VERSION 5.7 ;
  NOWIREEXTENSIONATPIN ON ;
  DIVIDERCHAR "/" ;
  BUSBITCHARS "[]" ;
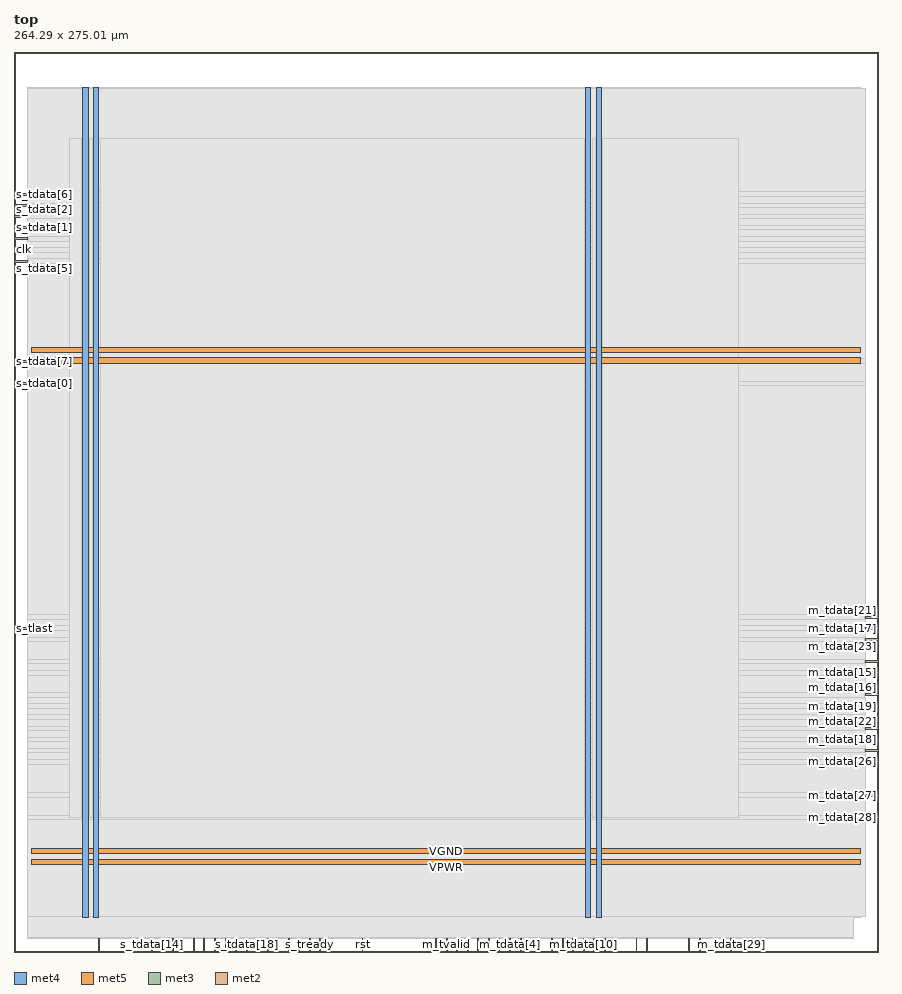
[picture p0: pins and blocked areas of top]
MACRO top
  CLASS BLOCK ;
  FOREIGN top ;
  ORIGIN 0.000 0.000 ;
  SIZE 264.290 BY 275.010 ;
  PIN VGND
    DIRECTION INOUT ;
    USE GROUND ;
    PORT
      LAYER met4 ;
        RECT 24.340 10.640 25.940 264.080 ;
    END
    PORT
      LAYER met4 ;
        RECT 177.940 10.640 179.540 264.080 ;
    END
    PORT
      LAYER met5 ;
        RECT 5.280 30.030 258.760 31.630 ;
    END
    PORT
      LAYER met5 ;
        RECT 5.280 183.210 258.760 184.810 ;
    END
  END VGND
  PIN VPWR
    DIRECTION INOUT ;
    USE POWER ;
    PORT
      LAYER met4 ;
        RECT 21.040 10.640 22.640 264.080 ;
    END
    PORT
      LAYER met4 ;
        RECT 174.640 10.640 176.240 264.080 ;
    END
    PORT
      LAYER met5 ;
        RECT 5.280 26.730 258.760 28.330 ;
    END
    PORT
      LAYER met5 ;
        RECT 5.280 179.910 258.760 181.510 ;
    END
  END VPWR
  PIN clk
    DIRECTION INPUT ;
    USE SIGNAL ;
    ANTENNAGATEAREA 0.852000 ;
    PORT
      LAYER met3 ;
        RECT 0.000 214.240 4.000 214.840 ;
    END
  END clk
  PIN m_tdata[0]
    DIRECTION OUTPUT ;
    USE SIGNAL ;
    ANTENNADIFFAREA 0.445500 ;
    PORT
      LAYER met2 ;
        RECT 138.550 0.000 138.830 4.000 ;
    END
  END m_tdata[0]
  PIN m_tdata[10]
    DIRECTION OUTPUT ;
    USE SIGNAL ;
    ANTENNADIFFAREA 0.445500 ;
    PORT
      LAYER met2 ;
        RECT 173.970 0.000 174.250 4.000 ;
    END
  END m_tdata[10]
  PIN m_tdata[11]
    DIRECTION OUTPUT ;
    USE SIGNAL ;
    ANTENNADIFFAREA 0.445500 ;
    PORT
      LAYER met2 ;
        RECT 177.190 0.000 177.470 4.000 ;
    END
  END m_tdata[11]
  PIN m_tdata[12]
    DIRECTION OUTPUT ;
    USE SIGNAL ;
    ANTENNADIFFAREA 0.445500 ;
    PORT
      LAYER met2 ;
        RECT 193.290 0.000 193.570 4.000 ;
    END
  END m_tdata[12]
  PIN m_tdata[13]
    DIRECTION OUTPUT ;
    USE SIGNAL ;
    ANTENNADIFFAREA 0.445500 ;
    PORT
      LAYER met2 ;
        RECT 190.070 0.000 190.350 4.000 ;
    END
  END m_tdata[13]
  PIN m_tdata[14]
    DIRECTION OUTPUT ;
    USE SIGNAL ;
    ANTENNADIFFAREA 0.445500 ;
    PORT
      LAYER met2 ;
        RECT 180.410 0.000 180.690 4.000 ;
    END
  END m_tdata[14]
  PIN m_tdata[15]
    DIRECTION OUTPUT ;
    USE SIGNAL ;
    ANTENNADIFFAREA 0.445500 ;
    PORT
      LAYER met3 ;
        RECT 260.290 85.040 264.290 85.640 ;
    END
  END m_tdata[15]
  PIN m_tdata[16]
    DIRECTION OUTPUT ;
    USE SIGNAL ;
    ANTENNADIFFAREA 0.445500 ;
    PORT
      LAYER met3 ;
        RECT 260.290 78.240 264.290 78.840 ;
    END
  END m_tdata[16]
  PIN m_tdata[17]
    DIRECTION OUTPUT ;
    USE SIGNAL ;
    ANTENNADIFFAREA 0.445500 ;
    PORT
      LAYER met3 ;
        RECT 260.290 98.640 264.290 99.240 ;
    END
  END m_tdata[17]
  PIN m_tdata[18]
    DIRECTION OUTPUT ;
    USE SIGNAL ;
    ANTENNADIFFAREA 0.445500 ;
    PORT
      LAYER met3 ;
        RECT 260.290 64.640 264.290 65.240 ;
    END
  END m_tdata[18]
  PIN m_tdata[19]
    DIRECTION OUTPUT ;
    USE SIGNAL ;
    ANTENNADIFFAREA 0.445500 ;
    PORT
      LAYER met3 ;
        RECT 260.290 74.840 264.290 75.440 ;
    END
  END m_tdata[19]
  PIN m_tdata[1]
    DIRECTION OUTPUT ;
    USE SIGNAL ;
    ANTENNADIFFAREA 0.445500 ;
    PORT
      LAYER met2 ;
        RECT 170.750 0.000 171.030 4.000 ;
    END
  END m_tdata[1]
  PIN m_tdata[20]
    DIRECTION OUTPUT ;
    USE SIGNAL ;
    ANTENNADIFFAREA 0.445500 ;
    PORT
      LAYER met3 ;
        RECT 260.290 61.240 264.290 61.840 ;
    END
  END m_tdata[20]
  PIN m_tdata[21]
    DIRECTION OUTPUT ;
    USE SIGNAL ;
    ANTENNADIFFAREA 0.445500 ;
    PORT
      LAYER met3 ;
        RECT 260.290 102.040 264.290 102.640 ;
    END
  END m_tdata[21]
  PIN m_tdata[22]
    DIRECTION OUTPUT ;
    USE SIGNAL ;
    ANTENNADIFFAREA 0.445500 ;
    PORT
      LAYER met3 ;
        RECT 260.290 68.040 264.290 68.640 ;
    END
  END m_tdata[22]
  PIN m_tdata[23]
    DIRECTION OUTPUT ;
    USE SIGNAL ;
    ANTENNADIFFAREA 0.445500 ;
    PORT
      LAYER met3 ;
        RECT 260.290 95.240 264.290 95.840 ;
    END
  END m_tdata[23]
  PIN m_tdata[24]
    DIRECTION OUTPUT ;
    USE SIGNAL ;
    ANTENNADIFFAREA 0.445500 ;
    PORT
      LAYER met3 ;
        RECT 260.290 88.440 264.290 89.040 ;
    END
  END m_tdata[24]
  PIN m_tdata[25]
    DIRECTION OUTPUT ;
    USE SIGNAL ;
    ANTENNADIFFAREA 0.445500 ;
    PORT
      LAYER met3 ;
        RECT 260.290 71.440 264.290 72.040 ;
    END
  END m_tdata[25]
  PIN m_tdata[26]
    DIRECTION OUTPUT ;
    USE SIGNAL ;
    ANTENNADIFFAREA 0.445500 ;
    PORT
      LAYER met3 ;
        RECT 260.290 57.840 264.290 58.440 ;
    END
  END m_tdata[26]
  PIN m_tdata[27]
    DIRECTION OUTPUT ;
    USE SIGNAL ;
    ANTENNADIFFAREA 0.445500 ;
    PORT
      LAYER met3 ;
        RECT 260.290 47.640 264.290 48.240 ;
    END
  END m_tdata[27]
  PIN m_tdata[28]
    DIRECTION OUTPUT ;
    USE SIGNAL ;
    ANTENNADIFFAREA 0.445500 ;
    PORT
      LAYER met3 ;
        RECT 260.290 40.840 264.290 41.440 ;
    END
  END m_tdata[28]
  PIN m_tdata[29]
    DIRECTION OUTPUT ;
    USE SIGNAL ;
    ANTENNADIFFAREA 0.445500 ;
    PORT
      LAYER met2 ;
        RECT 219.050 0.000 219.330 4.000 ;
    END
  END m_tdata[29]
  PIN m_tdata[2]
    DIRECTION OUTPUT ;
    USE SIGNAL ;
    ANTENNADIFFAREA 0.445500 ;
    PORT
      LAYER met2 ;
        RECT 148.210 0.000 148.490 4.000 ;
    END
  END m_tdata[2]
  PIN m_tdata[30]
    DIRECTION OUTPUT ;
    USE SIGNAL ;
    ANTENNADIFFAREA 0.445500 ;
    PORT
      LAYER met2 ;
        RECT 209.390 0.000 209.670 4.000 ;
    END
  END m_tdata[30]
  PIN m_tdata[31]
    DIRECTION OUTPUT ;
    USE SIGNAL ;
    ANTENNADIFFAREA 0.445500 ;
    PORT
      LAYER met2 ;
        RECT 206.170 0.000 206.450 4.000 ;
    END
  END m_tdata[31]
  PIN m_tdata[3]
    DIRECTION OUTPUT ;
    USE SIGNAL ;
    ANTENNADIFFAREA 0.445500 ;
    PORT
      LAYER met2 ;
        RECT 154.650 0.000 154.930 4.000 ;
    END
  END m_tdata[3]
  PIN m_tdata[4]
    DIRECTION OUTPUT ;
    USE SIGNAL ;
    ANTENNADIFFAREA 0.445500 ;
    PORT
      LAYER met2 ;
        RECT 151.430 0.000 151.710 4.000 ;
    END
  END m_tdata[4]
  PIN m_tdata[5]
    DIRECTION OUTPUT ;
    USE SIGNAL ;
    ANTENNADIFFAREA 0.445500 ;
    PORT
      LAYER met2 ;
        RECT 135.330 0.000 135.610 4.000 ;
    END
  END m_tdata[5]
  PIN m_tdata[6]
    DIRECTION OUTPUT ;
    USE SIGNAL ;
    ANTENNADIFFAREA 0.445500 ;
    PORT
      LAYER met2 ;
        RECT 141.770 0.000 142.050 4.000 ;
    END
  END m_tdata[6]
  PIN m_tdata[7]
    DIRECTION OUTPUT ;
    USE SIGNAL ;
    ANTENNADIFFAREA 0.445500 ;
    PORT
      LAYER met2 ;
        RECT 144.990 0.000 145.270 4.000 ;
    END
  END m_tdata[7]
  PIN m_tdata[8]
    DIRECTION OUTPUT ;
    USE SIGNAL ;
    ANTENNADIFFAREA 0.445500 ;
    PORT
      LAYER met2 ;
        RECT 164.310 0.000 164.590 4.000 ;
    END
  END m_tdata[8]
  PIN m_tdata[9]
    DIRECTION OUTPUT ;
    USE SIGNAL ;
    ANTENNADIFFAREA 0.445500 ;
    PORT
      LAYER met2 ;
        RECT 167.530 0.000 167.810 4.000 ;
    END
  END m_tdata[9]
  PIN m_tready
    DIRECTION INPUT ;
    USE SIGNAL ;
    ANTENNAGATEAREA 0.196500 ;
    PORT
      LAYER met2 ;
        RECT 128.890 0.000 129.170 4.000 ;
    END
  END m_tready
  PIN m_tvalid
    DIRECTION OUTPUT ;
    USE SIGNAL ;
    ANTENNADIFFAREA 0.445500 ;
    PORT
      LAYER met2 ;
        RECT 132.110 0.000 132.390 4.000 ;
    END
  END m_tvalid
  PIN rst
    DIRECTION INPUT ;
    USE SIGNAL ;
    ANTENNAGATEAREA 0.159000 ;
    PORT
      LAYER met2 ;
        RECT 106.350 0.000 106.630 4.000 ;
    END
  END rst
  PIN s_tdata[0]
    DIRECTION INPUT ;
    USE SIGNAL ;
    ANTENNAGATEAREA 0.196500 ;
    PORT
      LAYER met3 ;
        RECT 0.000 173.440 4.000 174.040 ;
    END
  END s_tdata[0]
  PIN s_tdata[10]
    DIRECTION INPUT ;
    USE SIGNAL ;
    ANTENNAGATEAREA 0.196500 ;
    PORT
      LAYER met2 ;
        RECT 87.030 0.000 87.310 4.000 ;
    END
  END s_tdata[10]
  PIN s_tdata[11]
    DIRECTION INPUT ;
    USE SIGNAL ;
    ANTENNAGATEAREA 0.213000 ;
    PORT
      LAYER met2 ;
        RECT 80.590 0.000 80.870 4.000 ;
    END
  END s_tdata[11]
  PIN s_tdata[12]
    DIRECTION INPUT ;
    USE SIGNAL ;
    ANTENNAGATEAREA 0.196500 ;
    PORT
      LAYER met2 ;
        RECT 61.270 0.000 61.550 4.000 ;
    END
  END s_tdata[12]
  PIN s_tdata[13]
    DIRECTION INPUT ;
    USE SIGNAL ;
    ANTENNAGATEAREA 0.196500 ;
    PORT
      LAYER met2 ;
        RECT 64.490 0.000 64.770 4.000 ;
    END
  END s_tdata[13]
  PIN s_tdata[14]
    DIRECTION INPUT ;
    USE SIGNAL ;
    ANTENNAGATEAREA 0.196500 ;
    PORT
      LAYER met2 ;
        RECT 41.950 0.000 42.230 4.000 ;
    END
  END s_tdata[14]
  PIN s_tdata[15]
    DIRECTION INPUT ;
    USE SIGNAL ;
    ANTENNAGATEAREA 0.126000 ;
    PORT
      LAYER met2 ;
        RECT 25.850 0.000 26.130 4.000 ;
    END
  END s_tdata[15]
  PIN s_tdata[16]
    DIRECTION INPUT ;
    USE SIGNAL ;
    ANTENNAGATEAREA 0.196500 ;
    PORT
      LAYER met2 ;
        RECT 54.830 0.000 55.110 4.000 ;
    END
  END s_tdata[16]
  PIN s_tdata[17]
    DIRECTION INPUT ;
    USE SIGNAL ;
    ANTENNAGATEAREA 0.196500 ;
    PORT
      LAYER met2 ;
        RECT 48.390 0.000 48.670 4.000 ;
    END
  END s_tdata[17]
  PIN s_tdata[18]
    DIRECTION INPUT ;
    USE SIGNAL ;
    ANTENNAGATEAREA 0.196500 ;
    PORT
      LAYER met2 ;
        RECT 70.930 0.000 71.210 4.000 ;
    END
  END s_tdata[18]
  PIN s_tdata[19]
    DIRECTION INPUT ;
    USE SIGNAL ;
    ANTENNAGATEAREA 0.196500 ;
    PORT
      LAYER met2 ;
        RECT 51.610 0.000 51.890 4.000 ;
    END
  END s_tdata[19]
  PIN s_tdata[1]
    DIRECTION INPUT ;
    USE SIGNAL ;
    ANTENNAGATEAREA 0.213000 ;
    PORT
      LAYER met3 ;
        RECT 0.000 221.040 4.000 221.640 ;
    END
  END s_tdata[1]
  PIN s_tdata[20]
    DIRECTION INPUT ;
    USE SIGNAL ;
    ANTENNAGATEAREA 0.196500 ;
    PORT
      LAYER met2 ;
        RECT 67.710 0.000 67.990 4.000 ;
    END
  END s_tdata[20]
  PIN s_tdata[21]
    DIRECTION INPUT ;
    USE SIGNAL ;
    ANTENNAGATEAREA 0.196500 ;
    PORT
      LAYER met2 ;
        RECT 74.150 0.000 74.430 4.000 ;
    END
  END s_tdata[21]
  PIN s_tdata[22]
    DIRECTION INPUT ;
    USE SIGNAL ;
    ANTENNAGATEAREA 0.126000 ;
    PORT
      LAYER met2 ;
        RECT 58.050 0.000 58.330 4.000 ;
    END
  END s_tdata[22]
  PIN s_tdata[23]
    DIRECTION INPUT ;
    USE SIGNAL ;
    ANTENNAGATEAREA 0.213000 ;
    PORT
      LAYER met2 ;
        RECT 45.170 0.000 45.450 4.000 ;
    END
  END s_tdata[23]
  PIN s_tdata[2]
    DIRECTION INPUT ;
    USE SIGNAL ;
    ANTENNAGATEAREA 0.159000 ;
    PORT
      LAYER met3 ;
        RECT 0.000 224.440 4.000 225.040 ;
    END
  END s_tdata[2]
  PIN s_tdata[3]
    DIRECTION INPUT ;
    USE SIGNAL ;
    ANTENNAGATEAREA 0.213000 ;
    PORT
      LAYER met3 ;
        RECT 0.000 217.640 4.000 218.240 ;
    END
  END s_tdata[3]
  PIN s_tdata[4]
    DIRECTION INPUT ;
    USE SIGNAL ;
    ANTENNAGATEAREA 0.213000 ;
    PORT
      LAYER met3 ;
        RECT 0.000 227.840 4.000 228.440 ;
    END
  END s_tdata[4]
  PIN s_tdata[5]
    DIRECTION INPUT ;
    USE SIGNAL ;
    ANTENNAGATEAREA 0.126000 ;
    PORT
      LAYER met3 ;
        RECT 0.000 210.840 4.000 211.440 ;
    END
  END s_tdata[5]
  PIN s_tdata[6]
    DIRECTION INPUT ;
    USE SIGNAL ;
    ANTENNAGATEAREA 0.196500 ;
    PORT
      LAYER met3 ;
        RECT 0.000 231.240 4.000 231.840 ;
    END
  END s_tdata[6]
  PIN s_tdata[7]
    DIRECTION INPUT ;
    USE SIGNAL ;
    ANTENNAGATEAREA 0.495000 ;
    PORT
      LAYER met3 ;
        RECT 0.000 180.240 4.000 180.840 ;
    END
  END s_tdata[7]
  PIN s_tdata[8]
    DIRECTION INPUT ;
    USE SIGNAL ;
    ANTENNAGATEAREA 0.159000 ;
    PORT
      LAYER met2 ;
        RECT 83.810 0.000 84.090 4.000 ;
    END
  END s_tdata[8]
  PIN s_tdata[9]
    DIRECTION INPUT ;
    USE SIGNAL ;
    ANTENNAGATEAREA 0.196500 ;
    PORT
      LAYER met2 ;
        RECT 77.370 0.000 77.650 4.000 ;
    END
  END s_tdata[9]
  PIN s_tlast
    DIRECTION INPUT ;
    USE SIGNAL ;
    ANTENNAGATEAREA 0.196500 ;
    PORT
      LAYER met3 ;
        RECT 0.000 98.640 4.000 99.240 ;
    END
  END s_tlast
  PIN s_tready
    DIRECTION OUTPUT ;
    USE SIGNAL ;
    ANTENNADIFFAREA 0.445500 ;
    PORT
      LAYER met2 ;
        RECT 90.250 0.000 90.530 4.000 ;
    END
  END s_tready
  PIN s_tvalid
    DIRECTION INPUT ;
    USE SIGNAL ;
    ANTENNAGATEAREA 0.213000 ;
    PORT
      LAYER met2 ;
        RECT 93.470 0.000 93.750 4.000 ;
    END
  END s_tvalid
  OBS
      LAYER nwell ;
        RECT 5.330 10.795 258.710 264.030 ;
      LAYER li1 ;
        RECT 5.520 10.795 258.520 263.925 ;
      LAYER met1 ;
        RECT 4.210 10.640 258.520 264.080 ;
      LAYER met2 ;
        RECT 4.230 4.280 256.590 264.025 ;
        RECT 4.230 4.000 25.570 4.280 ;
        RECT 26.410 4.000 41.670 4.280 ;
        RECT 42.510 4.000 44.890 4.280 ;
        RECT 45.730 4.000 48.110 4.280 ;
        RECT 48.950 4.000 51.330 4.280 ;
        RECT 52.170 4.000 54.550 4.280 ;
        RECT 55.390 4.000 57.770 4.280 ;
        RECT 58.610 4.000 60.990 4.280 ;
        RECT 61.830 4.000 64.210 4.280 ;
        RECT 65.050 4.000 67.430 4.280 ;
        RECT 68.270 4.000 70.650 4.280 ;
        RECT 71.490 4.000 73.870 4.280 ;
        RECT 74.710 4.000 77.090 4.280 ;
        RECT 77.930 4.000 80.310 4.280 ;
        RECT 81.150 4.000 83.530 4.280 ;
        RECT 84.370 4.000 86.750 4.280 ;
        RECT 87.590 4.000 89.970 4.280 ;
        RECT 90.810 4.000 93.190 4.280 ;
        RECT 94.030 4.000 106.070 4.280 ;
        RECT 106.910 4.000 128.610 4.280 ;
        RECT 129.450 4.000 131.830 4.280 ;
        RECT 132.670 4.000 135.050 4.280 ;
        RECT 135.890 4.000 138.270 4.280 ;
        RECT 139.110 4.000 141.490 4.280 ;
        RECT 142.330 4.000 144.710 4.280 ;
        RECT 145.550 4.000 147.930 4.280 ;
        RECT 148.770 4.000 151.150 4.280 ;
        RECT 151.990 4.000 154.370 4.280 ;
        RECT 155.210 4.000 164.030 4.280 ;
        RECT 164.870 4.000 167.250 4.280 ;
        RECT 168.090 4.000 170.470 4.280 ;
        RECT 171.310 4.000 173.690 4.280 ;
        RECT 174.530 4.000 176.910 4.280 ;
        RECT 177.750 4.000 180.130 4.280 ;
        RECT 180.970 4.000 189.790 4.280 ;
        RECT 190.630 4.000 193.010 4.280 ;
        RECT 193.850 4.000 205.890 4.280 ;
        RECT 206.730 4.000 209.110 4.280 ;
        RECT 209.950 4.000 218.770 4.280 ;
        RECT 219.610 4.000 256.590 4.280 ;
      LAYER met3 ;
        RECT 3.990 232.240 260.290 264.005 ;
        RECT 4.400 230.840 260.290 232.240 ;
        RECT 3.990 228.840 260.290 230.840 ;
        RECT 4.400 227.440 260.290 228.840 ;
        RECT 3.990 225.440 260.290 227.440 ;
        RECT 4.400 224.040 260.290 225.440 ;
        RECT 3.990 222.040 260.290 224.040 ;
        RECT 4.400 220.640 260.290 222.040 ;
        RECT 3.990 218.640 260.290 220.640 ;
        RECT 4.400 217.240 260.290 218.640 ;
        RECT 3.990 215.240 260.290 217.240 ;
        RECT 4.400 213.840 260.290 215.240 ;
        RECT 3.990 211.840 260.290 213.840 ;
        RECT 4.400 210.440 260.290 211.840 ;
        RECT 3.990 181.240 260.290 210.440 ;
        RECT 4.400 179.840 260.290 181.240 ;
        RECT 3.990 174.440 260.290 179.840 ;
        RECT 4.400 173.040 260.290 174.440 ;
        RECT 3.990 103.040 260.290 173.040 ;
        RECT 3.990 101.640 259.890 103.040 ;
        RECT 3.990 99.640 260.290 101.640 ;
        RECT 4.400 98.240 259.890 99.640 ;
        RECT 3.990 96.240 260.290 98.240 ;
        RECT 3.990 94.840 259.890 96.240 ;
        RECT 3.990 89.440 260.290 94.840 ;
        RECT 3.990 88.040 259.890 89.440 ;
        RECT 3.990 86.040 260.290 88.040 ;
        RECT 3.990 84.640 259.890 86.040 ;
        RECT 3.990 79.240 260.290 84.640 ;
        RECT 3.990 77.840 259.890 79.240 ;
        RECT 3.990 75.840 260.290 77.840 ;
        RECT 3.990 74.440 259.890 75.840 ;
        RECT 3.990 72.440 260.290 74.440 ;
        RECT 3.990 71.040 259.890 72.440 ;
        RECT 3.990 69.040 260.290 71.040 ;
        RECT 3.990 67.640 259.890 69.040 ;
        RECT 3.990 65.640 260.290 67.640 ;
        RECT 3.990 64.240 259.890 65.640 ;
        RECT 3.990 62.240 260.290 64.240 ;
        RECT 3.990 60.840 259.890 62.240 ;
        RECT 3.990 58.840 260.290 60.840 ;
        RECT 3.990 57.440 259.890 58.840 ;
        RECT 3.990 48.640 260.290 57.440 ;
        RECT 3.990 47.240 259.890 48.640 ;
        RECT 3.990 41.840 260.290 47.240 ;
        RECT 3.990 40.440 259.890 41.840 ;
        RECT 3.990 10.715 260.290 40.440 ;
      LAYER met4 ;
        RECT 16.855 40.975 20.640 248.705 ;
        RECT 23.040 40.975 23.940 248.705 ;
        RECT 26.340 40.975 174.240 248.705 ;
        RECT 176.640 40.975 177.540 248.705 ;
        RECT 179.940 40.975 221.425 248.705 ;
  END
END top
END LIBRARY

